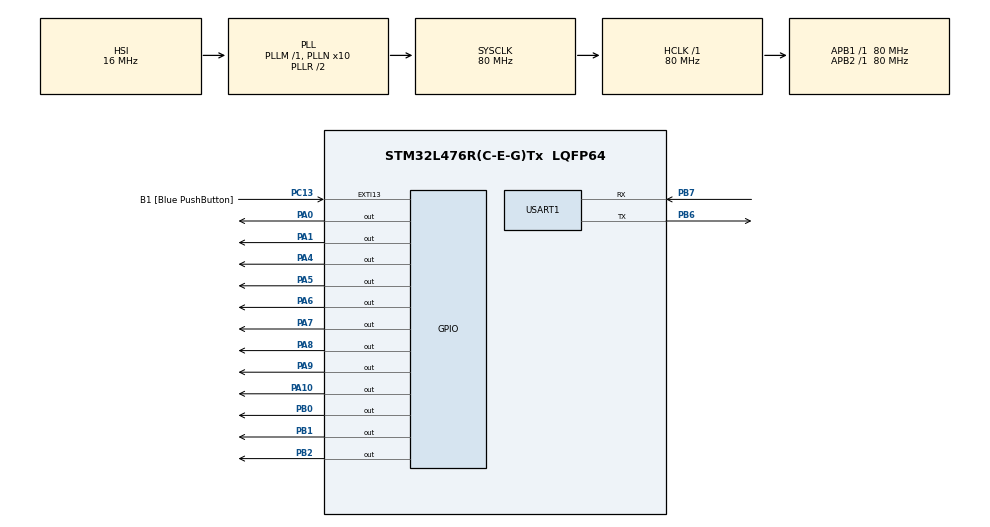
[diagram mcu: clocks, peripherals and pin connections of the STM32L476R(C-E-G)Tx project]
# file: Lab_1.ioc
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Mcu.Family=STM32L4
Mcu.Name=STM32L476R(C-E-G)Tx
Mcu.Package=LQFP64
NVIC.PriorityGroup=NVIC_PRIORITYGROUP_4
NVIC.USART1_IRQn=true\:0\:0\:false\:false\:true\:true\:true\:true
PA0.Signal=GPIO_Output
PA1.Signal=GPIO_Output
PA10.Signal=GPIO_Output
PA13\ (JTMS-SWDIO).GPIO_Label=TMS
PA13\ (JTMS-SWDIO).Mode=Serial_Wire
PA13\ (JTMS-SWDIO).Signal=SYS_JTMS-SWDIO
PA14\ (JTCK-SWCLK).GPIO_Label=TCK
PA14\ (JTCK-SWCLK).Mode=Serial_Wire
PA14\ (JTCK-SWCLK).Signal=SYS_JTCK-SWCLK
PA2.Signal=USART2_TX
PA3.Signal=USART2_RX
PA4.Signal=GPIO_Output
PA5.Signal=GPIO_Output
PA6.Signal=GPIO_Output
PA7.Signal=GPIO_Output
PA8.Signal=GPIO_Output
PA9.Signal=GPIO_Output
PB0.Signal=GPIO_Output
PB1.Signal=GPIO_Output
PB2.Signal=GPIO_Output
PB3\ (JTDO-TRACESWO).GPIO_Label=SWO
PB3\ (JTDO-TRACESWO).Signal=SYS_JTDO-SWO
PB6.Mode=Asynchronous
PB6.Signal=USART1_TX
PB7.Mode=Asynchronous
PB7.Signal=USART1_RX
PC13.GPIO_Label=B1 [Blue PushButton]
PC13.GPIO_ModeDefaultEXTI=GPIO_MODE_IT_FALLING
PC13.GPIO_PuPd=GPIO_NOPULL
PC13.Signal=GPXTI13
PC14-OSC32_IN\ (PC14).Mode=LSE-External-Oscillator
PC14-OSC32_IN\ (PC14).Signal=RCC_OSC32_IN
PC15-OSC32_OUT\ (PC15).Mode=LSE-External-Oscillator
PC15-OSC32_OUT\ (PC15).Signal=RCC_OSC32_OUT
PH0-OSC_IN\ (PH0).Signal=RCC_OSC_IN
PH1-OSC_OUT\ (PH1).Signal=RCC_OSC_OUT
ProjectManager.HeapSize=0x200
ProjectManager.StackSize=0x400
ProjectManager.TargetToolchain=STM32CubeIDE
RCC.ADCFreq_Value=64000000
RCC.AHBFreq_Value=80000000
RCC.APB1Freq_Value=80000000
RCC.APB1TimFreq_Value=80000000
RCC.APB2Freq_Value=80000000
RCC.APB2TimFreq_Value=80000000
RCC.CortexFreq_Value=80000000
RCC.HCLKFreq_Value=80000000
RCC.HSE_VALUE=8000000
RCC.HSI_VALUE=16000000
RCC.MSI_VALUE=4000000
RCC.PLLN=10
RCC.PLLSourceVirtual=RCC_PLLSOURCE_HSI
RCC.PREFETCH_ENABLE=1
RCC.SYSCLKFreq_VALUE=80000000
RCC.SYSCLKSource=RCC_SYSCLKSOURCE_PLLCLK
RCC.USBFreq_Value=64000000
RCC.VCOOutputFreq_Value=160000000
USART1.VirtualMode-Asynchronous=VM_ASYNC
board=NUCLEO-L476RG

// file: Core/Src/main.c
#include "main.h"

UART_HandleTypeDef huart1;
uint8_t rx_byte;

/* USER CODE BEGIN PV */
// Motor control prototypes
void stopMotors(void);
void forward(void);
void backward(void);
void left(void);
void right(void);
/* USER CODE END PV */

void SystemClock_Config(void);
static void MX_GPIO_Init(void);
static void MX_USART1_UART_Init(void);

/* USER CODE BEGIN 0 */

// -------- Motor Control Functions --------
void stopMotors(void)
{
    HAL_GPIO_WritePin(GPIOA, ENA_Pin|ENB_Pin, GPIO_PIN_RESET);
    HAL_GPIO_WritePin(GPIOA, IN1_Pin|IN2_Pin|IN3_Pin|IN4_Pin, GPIO_PIN_RESET);
}

void forward(void) {
    // Enable both motors
    HAL_GPIO_WritePin(GPIOA, ENA_Pin, GPIO_PIN_SET);
    HAL_GPIO_WritePin(GPIOA, ENB_Pin, GPIO_PIN_SET);

    // Motor A forward
    HAL_GPIO_WritePin(GPIOA, IN1_Pin, GPIO_PIN_SET);
    HAL_GPIO_WritePin(GPIOA, IN2_Pin, GPIO_PIN_RESET);

    // Motor B forward
    HAL_GPIO_WritePin(GPIOA, IN3_Pin, GPIO_PIN_SET);
    HAL_GPIO_WritePin(GPIOA, IN4_Pin, GPIO_PIN_RESET);
}

void backward(void) {
    HAL_GPIO_WritePin(GPIOA, ENA_Pin, GPIO_PIN_SET);
    HAL_GPIO_WritePin(GPIOA, ENB_Pin, GPIO_PIN_SET);

    HAL_GPIO_WritePin(GPIOA, IN1_Pin, GPIO_PIN_RESET);
    HAL_GPIO_WritePin(GPIOA, IN2_Pin, GPIO_PIN_SET);

    HAL_GPIO_WritePin(GPIOA, IN3_Pin, GPIO_PIN_RESET);
    HAL_GPIO_WritePin(GPIOA, IN4_Pin, GPIO_PIN_SET);
}

void left(void) {
    HAL_GPIO_WritePin(GPIOA, ENA_Pin, GPIO_PIN_SET);
    HAL_GPIO_WritePin(GPIOA, ENB_Pin, GPIO_PIN_SET);

    HAL_GPIO_WritePin(GPIOA, IN1_Pin, GPIO_PIN_RESET);
    HAL_GPIO_WritePin(GPIOA, IN2_Pin, GPIO_PIN_SET);

    HAL_GPIO_WritePin(GPIOA, IN3_Pin, GPIO_PIN_SET);
    HAL_GPIO_WritePin(GPIOA, IN4_Pin, GPIO_PIN_RESET);
}

void right(void) {
    HAL_GPIO_WritePin(GPIOA, ENA_Pin, GPIO_PIN_SET);
    HAL_GPIO_WritePin(GPIOA, ENB_Pin, GPIO_PIN_SET);

    HAL_GPIO_WritePin(GPIOA, IN1_Pin, GPIO_PIN_SET);
    HAL_GPIO_WritePin(GPIOA, IN2_Pin, GPIO_PIN_RESET);

    HAL_GPIO_WritePin(GPIOA, IN3_Pin, GPIO_PIN_RESET);
    HAL_GPIO_WritePin(GPIOA, IN4_Pin, GPIO_PIN_SET);
}

// UART RX interrupt callback
void HAL_UART_RxCpltCallback(UART_HandleTypeDef *huart)
{
    if (huart->Instance == USART1)
    {
        switch (rx_byte)
        {
            case 'F': forward(); break;
            case 'B': backward(); break;
            case 'L': left(); break;
            case 'R': right(); break;
            case 'S': stopMotors(); break;
        }

        HAL_UART_Receive_IT(&huart1, &rx_byte, 1);
    }
}

/* USER CODE END 0 */

int main(void)
{
  HAL_Init();

  SystemClock_Config();
  MX_GPIO_Init();
  MX_USART1_UART_Init();

  stopMotors();

  HAL_UART_Receive_IT(&huart1, &rx_byte, 1);

  while (1)
  {
      // interrupt driven
  }
}

/* --------------------------------------------------------------------------
   SYSTEM CLOCK CONFIG  (CubeMX generated)
   --------------------------------------------------------------------------*/
void SystemClock_Config(void)
{
  RCC_OscInitTypeDef RCC_OscInitStruct = {0};
  RCC_ClkInitTypeDef RCC_ClkInitStruct = {0};

  __HAL_RCC_PWR_CLK_ENABLE();
  HAL_PWREx_ControlVoltageScaling(PWR_REGULATOR_VOLTAGE_SCALE1);

  RCC_OscInitStruct.OscillatorType = RCC_OSCILLATORTYPE_HSI;
  RCC_OscInitStruct.HSIState = RCC_HSI_ON;
  RCC_OscInitStruct.HSICalibrationValue = RCC_HSICALIBRATION_DEFAULT;
  RCC_OscInitStruct.PLL.PLLState = RCC_PLL_ON;
  RCC_OscInitStruct.PLL.PLLSource = RCC_PLLSOURCE_HSI;
  RCC_OscInitStruct.PLL.PLLM = 1;
  RCC_OscInitStruct.PLL.PLLN = 10;
  RCC_OscInitStruct.PLL.PLLP = RCC_PLLP_DIV7;
  RCC_OscInitStruct.PLL.PLLQ = RCC_PLLQ_DIV2;
  RCC_OscInitStruct.PLL.PLLR = RCC_PLLR_DIV2;

  if (HAL_RCC_OscConfig(&RCC_OscInitStruct) != HAL_OK)
    Error_Handler();

  RCC_ClkInitStruct.ClockType = RCC_CLOCKTYPE_HCLK|RCC_CLOCKTYPE_SYSCLK
                               |RCC_CLOCKTYPE_PCLK1|RCC_CLOCKTYPE_PCLK2;
  RCC_ClkInitStruct.SYSCLKSource = RCC_SYSCLKSOURCE_PLLCLK;
  RCC_ClkInitStruct.AHBCLKDivider = RCC_SYSCLK_DIV1;
  RCC_ClkInitStruct.APB1CLKDivider = RCC_HCLK_DIV1;
  RCC_ClkInitStruct.APB2CLKDivider = RCC_HCLK_DIV1;

  if (HAL_RCC_ClockConfig(&RCC_ClkInitStruct, FLASH_LATENCY_4) != HAL_OK)
    Error_Handler();
}

/* --------------------------------------------------------------------------
   GPIO INIT  (CubeMX generated)
   --------------------------------------------------------------------------*/
static void MX_GPIO_Init(void)
{
  GPIO_InitTypeDef GPIO_InitStruct = {0};

  __HAL_RCC_GPIOA_CLK_ENABLE();

  GPIO_InitStruct.Pin = ENA_Pin | IN1_Pin | IN2_Pin |
                        IN3_Pin | IN4_Pin | ENB_Pin;

  GPIO_InitStruct.Mode = GPIO_MODE_OUTPUT_PP;
  GPIO_InitStruct.Pull = GPIO_NOPULL;
  GPIO_InitStruct.Speed = GPIO_SPEED_FREQ_LOW;

  HAL_GPIO_Init(GPIOA, &GPIO_InitStruct);

  HAL_GPIO_WritePin(GPIOA, ENA_Pin|IN1_Pin|IN2_Pin|IN3_Pin|IN4_Pin|ENB_Pin, GPIO_PIN_RESET);
}

/* --------------------------------------------------------------------------
   USART1 INIT  (CubeMX generated)
   --------------------------------------------------------------------------*/
static void MX_USART1_UART_Init(void)
{
  huart1.Instance = USART1;
  huart1.Init.BaudRate = 115200;
  huart1.Init.WordLength = UART_WORDLENGTH_8B;
  huart1.Init.StopBits = UART_STOPBITS_1;
  huart1.Init.Parity = UART_PARITY_NONE;
  huart1.Init.Mode = UART_MODE_TX_RX;
  huart1.Init.HwFlowCtl = UART_HWCONTROL_NONE;
  huart1.Init.OverSampling = UART_OVERSAMPLING_16;

  if (HAL_UART_Init(&huart1) != HAL_OK)
    Error_Handler();
}

void Error_Handler(void)
{
  __disable_irq();
  while (1) {}
}
